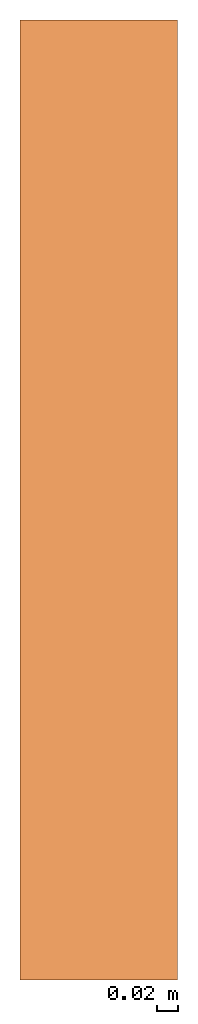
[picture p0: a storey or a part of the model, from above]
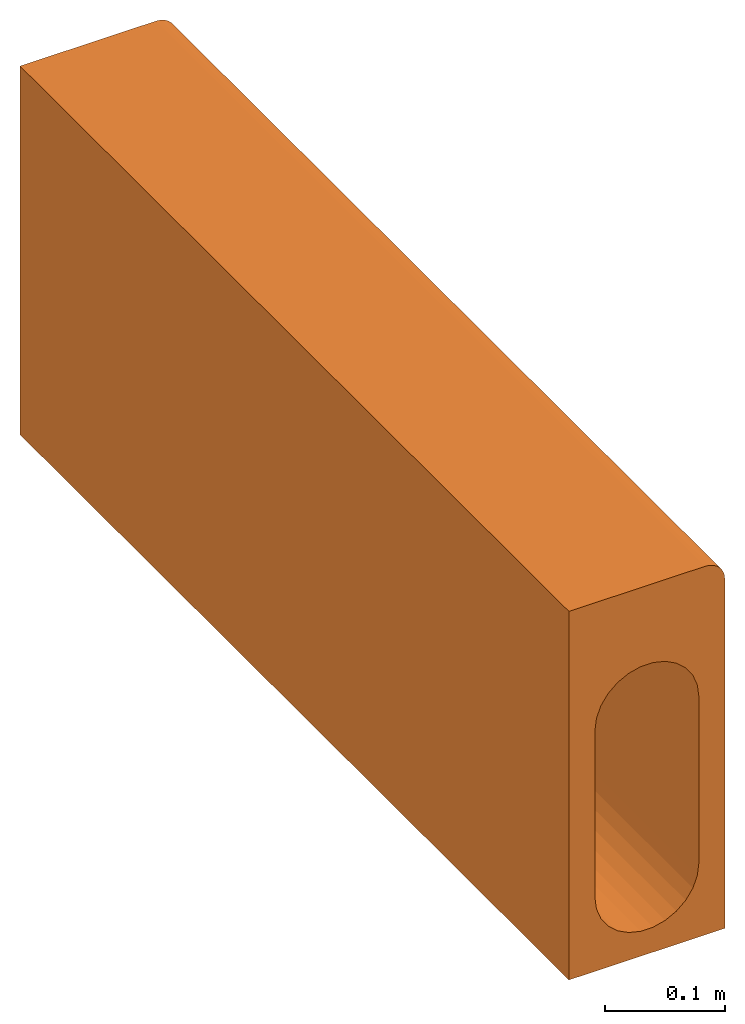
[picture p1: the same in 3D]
Properties of the parts of a building model (IFC2X3)

# File
Description: ViewDefinition [CoordinationView]
File name: 4933 - Centre Stone - 915mm LG.ifc
Time: 2013-09-18T16:22:40
Written by: Autodesk Revit 2013
Made in: 20120221_2030(x64)

# IfcProject, Project Number
LongName: Project Name; Phase: Project Status

# IfcSite, Default
RefLatitude: 42, 21, 30, 344238; RefLongitude: -71, -3, -35, -194702; RefElevation: 0 mm

# IfcBuilding
Pset_BuildingCommon - NumberOfStoreys: 2
Other - Client Name: Owner; Project Number: Project Number; Project Status: Project Status; Project Address: Enter address here; Project Name: Project Name; Project Issue Date: Issue Date

# IfcBuildingStorey (2)
Constraints - Elevation Base: 0
Graphics - Symbol: M_Level Head - Circle: M_Level Head - Circle; Line Pattern: Center; Line Weight: 1; Symbol at End 1 Default: no; Color: 0; Symbol at End 2 Default: yes
Identity Data - Structural: no; Building Story: yes
Dimensions - Computation Height: 0 mm
Name | LongName = Name | Elevation (mm) = Constraints, Elevation (mm)
T.O. Fnd. Wall | T.O. Fnd. Wall | -300
Level 1 | Level 1 | 0

# IfcBuildingElementProxy: 4933 - Centre Stone - 915mm LG, Civil-Drainage-Channel-ACO-KerbDrain-HB480(amar):4933 - Centre Stone - 915mm LG:4933 - Centre Stone - 915mm LG:481515
In: T.O. Fnd. Wall
Material: ACO Polymer Concrete.
Green Building Properties - Access Cover/Frame Recycled Material Content: N/A; End Cap Recyclable: N/A; End Cap Recycled Material Content: N/A; Access Cover/Frame Recyclable: N/A; Channel Recycled Material Content: 20% minimum; Channel Recyclable: Fully recyclable
Construction - Bus stop kerb: no; LH drop kerb: no; Closing end cap: no; 10-8m external mitre: no; LH BS transition kerb: no; Junction channel: no; perforated centre stone: no; Junction access unit: no; Junction end cap: no; cable loop: no; RH drop kerb: no; 25-11m external mitre: no; RH inlet/outlet end cap: no; 7-6m external mitre: no; Centre Stone: yes; RH BS transition kerb: no; KDHB480 500_blindunit: no; HB480-500: no; LH inlet/outlet end cap: no; 25-11m internal mitre: no; Access Unit: no
Other - Revision: 1; CreatedBy: www.aco.co.uk
Constraints - Moves With Nearby Elements: no; Level: Level: Level 1
Phasing - Phase Created: Phase 1
Dimensions - Volume: 28656784 mm3; Mitre Void End: -6770 mm; junction void depth: 2000 mm; Void Start I/O: 0 mm; Junction Start: 0 mm; Straight Void Start: 0 mm; Mitre Small End: 487 mm; Void End I/O: 150 mm; Junction End: 150 mm; Void Length: 915 mm; Mitre Void Start: -6765 mm; Mitre Long end: 500 mm; Void Depth: -355 mm; I/O endcap void depth: 2000 mm; Void Width: 150 mm
Pset_BuildingElementProxyCommon - Reference: 4933 - Centre Stone - 915mm LG
Data - Product Dimensions: 915mm x 150mm x 375mm (LxWxH); ACO Hydraulic Design Software: http://www.acodesign.co.uk; Product Weight: 59.8 Kg; Load Class: A 15 - D 400; Concrete Surround Volume - Load Class A 15 - D 400 - Concrete Pavement: N/A; Connection Pipe O.D: N/A; Channel C.S.A: 0.02mm²; Product Standard: BS EN 1433:2002, CE marked, Kitemarked; Installation - Concrete Grade: Refer to brochure; Invert Depth: 350mm; Drainage Slot Width: N/A; Concrete Surround Volume - Load Class A 15 - D 400 - Grass or Asphalt Pavement: N/A; Hydraulic Performance: http://www.aco.co.uk/download.php?id=120; Drainage Slot Intake area: N/A
Identity Data - Product Code: 4933; Address: ACO Business Park, Hitchin Road, Shefford, Bedfordshire, United Kingdom SG17 5TE; Installation guidelines: http://www.aco.co.uk/download.php?id=120; Product Page URL: http://www.aco.co.uk/product_detail.php?id=3; Assembly Code: D2040; Assembly Description: Rain Water Drainage; Cost: 0; OmniClass Number: 23.70.50.24; OmniClass Title: Rainwater Removal; Model: ACO KerbDrain HB480; URL: www.aco.co.uk; Model Description: Combined kerb and drainage system; Type Comments: ACO KerbDrain HB480 half battered centre stone unit c/w 25mm upstand 915mm long; e-mail Technical: technical@aco.co.uk; Fax: +44 (0)1462 815895; Product brochure: http://www.aco.co.uk/download.php?id=120; Manufacturer: ACO Technologies plc - ACO Water Management Division; Price: POA - contact ACO; Telephone: +44 (0)1462 816666; Maintenance guidelines: http://www.aco.co.uk/download.php?id=120; e-mail Sales: customersupport@aco.co.uk
General - TagNumber: 0.000000; SerialNumber: 0.000000
Materials and Finishes - Channel Colour: Grey; Connection Pipe Material Colour: N/A; End Cap Material: N/A; End Cap Colour: N/A; Access Cover/Frame Finish: N/A; Access Cover/Frame Material: N/A; Channel Material: Vienite® Synthetic Resin Concrete; Access Cover/Frame Colour: N/A; Connection Pipe Material: N/A

# IfcOpeningElement: Opening (3)
In: Level 1
Dimensions - Volume: 2311976250 mm3; Perimeter: 9790 mm; Thickness: 400 mm; Area: 5901750 mm2
Constraints - Level: Level: Level 1; Related to Mass: no; Height Offset From Level: 0 mm; Room Bounding: yes
Phasing - Phase Created: Phase 1
Structural - Enable Analytical Model: no; Structural: no
Construction - Function: 0; Default Thickness: 400 mm
Analytical Properties - Thermal mass: 543920; Thermal Resistance (R): 0.477897; Roughness: 1; Heat Transfer Coefficient (U): 2.0925; Absorptance: 0.1
Graphics - Coarse Scale Fill Color: 0
Materials and Finishes - Structural Material: Earth

# IfcSlab: Floor:Generic Floor - 400mm, Floor:Generic Floor - 400mm:136426
In: Level 1
PredefinedType: FLOOR; Material: Earth 400 mm
Dimensions - Volume: 2311976250 mm3; Perimeter: 9790 mm; Thickness: 400 mm; Area: 5901750 mm2
Constraints - Level: Level: Level 1; Related to Mass: no; Height Offset From Level: 0 mm; Room Bounding: yes
Phasing - Phase Created: Phase 1
Structural - Enable Analytical Model: no; Structural: no
Pset_SlabCommon - Reference: Generic Floor - 400mm; IsExternal: no; LoadBearing: yes
Construction - Function: 0; Default Thickness: 400 mm
Analytical Properties - Thermal mass: 543920; Thermal Resistance (R): 0.477897; Roughness: 1; Heat Transfer Coefficient (U): 2.0925; Absorptance: 0.1
Graphics - Coarse Scale Fill Color: 0
Materials and Finishes - Structural Material: Earth
